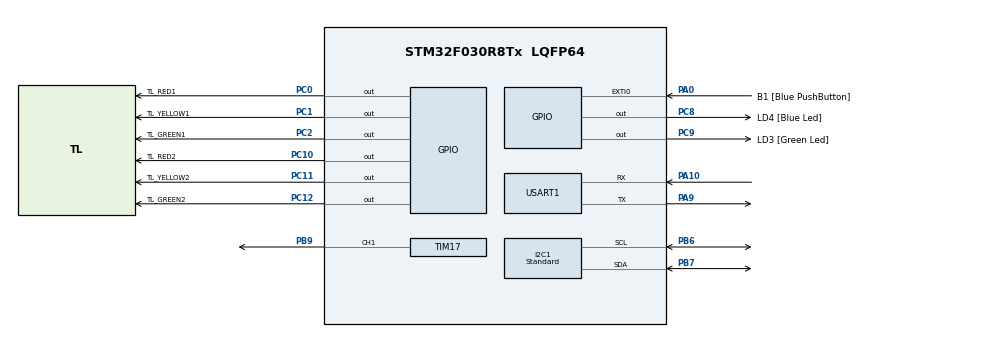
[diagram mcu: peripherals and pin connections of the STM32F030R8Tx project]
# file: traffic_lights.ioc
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Dma.Request0=USART1_RX
Dma.Request1=USART1_TX
Dma.USART1_RX.0.Direction=DMA_PERIPH_TO_MEMORY
Dma.USART1_RX.0.Instance=DMA1_Channel3
Dma.USART1_RX.0.MemDataAlignment=DMA_MDATAALIGN_BYTE
Dma.USART1_RX.0.MemInc=DMA_MINC_ENABLE
Dma.USART1_RX.0.Mode=DMA_NORMAL
Dma.USART1_RX.0.PeriphDataAlignment=DMA_PDATAALIGN_BYTE
Dma.USART1_RX.0.PeriphInc=DMA_PINC_DISABLE
Dma.USART1_RX.0.Priority=DMA_PRIORITY_LOW
Dma.USART1_TX.1.Direction=DMA_MEMORY_TO_PERIPH
Dma.USART1_TX.1.Instance=DMA1_Channel2
Dma.USART1_TX.1.MemDataAlignment=DMA_MDATAALIGN_BYTE
Dma.USART1_TX.1.MemInc=DMA_MINC_ENABLE
Dma.USART1_TX.1.Mode=DMA_NORMAL
Dma.USART1_TX.1.PeriphDataAlignment=DMA_PDATAALIGN_BYTE
Dma.USART1_TX.1.PeriphInc=DMA_PINC_DISABLE
Dma.USART1_TX.1.Priority=DMA_PRIORITY_LOW
I2C1.I2C_Speed_Mode=I2C_Standard
Mcu.Family=STM32F0
Mcu.Name=STM32F030R8Tx
Mcu.Package=LQFP64
NVIC.DMA1_Channel2_3_IRQn=true\:0\:0\:false\:true\:true\:2\:false\:true
NVIC.EXTI0_1_IRQn=true\:0\:0\:false\:true\:true\:3\:true\:true
NVIC.TIM16_IRQn=true\:0\:0\:false\:false\:true\:true\:true
NVIC.TIM6_IRQn=true\:0\:0\:false\:true\:true\:1\:true\:true
NVIC.USART1_IRQn=true\:0\:0\:false\:false\:true\:true\:true
PA0.GPIO_Label=B1 [Blue PushButton]
PA0.GPIO_ModeDefaultEXTI=GPIO_MODE_IT_FALLING
PA0.GPIO_PuPd=GPIO_NOPULL
PA0.Signal=GPXTI0
PA10.Mode=Asynchronous
PA10.Signal=USART1_RX
PA13.GPIO_Label=SWDIO
PA13.Mode=Serial_Wire
PA13.Signal=SYS_SWDIO
PA14.GPIO_Label=SWCLK
PA14.Mode=Serial_Wire
PA14.Signal=SYS_SWCLK
PA9.Mode=Asynchronous
PA9.Signal=USART1_TX
PB6.Mode=I2C
PB6.Signal=I2C1_SCL
PB7.Mode=I2C
PB7.Signal=I2C1_SDA
PB9.Signal=S_TIM17_CH1
PC0.GPIO_Label=TL_RED1
PC0.PinState=GPIO_PIN_SET
PC0.Signal=GPIO_Output
PC1.GPIO_Label=TL_YELLOW1
PC1.PinState=GPIO_PIN_SET
PC1.Signal=GPIO_Output
PC10.GPIO_Label=TL_RED2
PC10.Signal=GPIO_Output
PC11.GPIO_Label=TL_YELLOW2
PC11.Signal=GPIO_Output
PC12.GPIO_Label=TL_GREEN2
PC12.Signal=GPIO_Output
PC2.GPIO_Label=TL_GREEN1
PC2.PinState=GPIO_PIN_SET
PC2.Signal=GPIO_Output
PC8.GPIO_Label=LD4 [Blue Led]
PC8.Signal=GPIO_Output
PC9.GPIO_Label=LD3 [Green Led]
PC9.Signal=GPIO_Output
ProjectManager.HeapSize=0x200
ProjectManager.StackSize=0x400
ProjectManager.TargetToolchain=EWARM V8.32
RCC.AHBFreq_Value=48000000
RCC.APB1Freq_Value=48000000
RCC.APB1TimFreq_Value=48000000
RCC.HCLKFreq_Value=48000000
RCC.PLLMUL=RCC_PLL_MUL12
RCC.SYSCLKFreq_VALUE=48000000
RCC.SYSCLKSource=RCC_SYSCLKSOURCE_PLLCLK
SH.S_TIM17_CH1.0=TIM17_CH1,PWM Generation1 CH1
TIM16.Period=2
TIM16.Prescaler=19-1
TIM17.Channel=TIM_CHANNEL_1
TIM17.Period=2
TIM17.Prescaler=19 - 1
TIM17.Pulse=4
TIM6.Period=599
TIM6.Prescaler=5999
USART1.VirtualMode-Asynchronous=VM_ASYNC
VP_TIM16_VS_ClockSourceINT.Mode=Enable_Timer
VP_TIM17_VS_ClockSourceINT.Mode=Enable_Timer
VP_TIM6_VS_ClockSourceINT.Mode=Enable_Timer
board=STM32F0308-DISCO

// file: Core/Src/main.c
/* USER CODE BEGIN Header */
/**
  ******************************************************************************
  * @file           : main.c
  * @brief          : Main program body
  ******************************************************************************
  * @attention
  *
  * <h2><center>&copy; Copyright (c) 2020 STMicroelectronics.
  * All rights reserved.</center></h2>
  *
  * This software component is licensed by ST under BSD 3-Clause license,
  * the "License"; You may not use this file except in compliance with the
  * License. You may obtain a copy of the License at:
  *                        opensource.org/licenses/BSD-3-Clause
  *
  ******************************************************************************
  */
/* USER CODE END Header */
#include "main.h"

/* USER CODE BEGIN Includes */
#include <stdio.h>
#include "amg8833_driver.h"
#include "mlx90614_driver.h"
/* USER CODE END Includes */

/* USER CODE BEGIN PD */
#define UART_STRING_LEN 7
/* USER CODE END PD */

I2C_HandleTypeDef hi2c1;

TIM_HandleTypeDef htim6;
TIM_HandleTypeDef htim16;
TIM_HandleTypeDef htim17;

UART_HandleTypeDef huart1;
DMA_HandleTypeDef hdma_usart1_rx;
DMA_HandleTypeDef hdma_usart1_tx;

/* USER CODE BEGIN PV */
tl_states_s sequence_counter;
trl_states_s color_counter;
uint16_t termo_pic[64];
uint32_t led_color_ram[WS2812B_LEDS];
/* USER CODE END PV */

void SystemClock_Config(void);
static void MX_GPIO_Init(void);
static void MX_DMA_Init(void);
static void MX_TIM6_Init(void);
static void MX_USART1_UART_Init(void);
static void MX_I2C1_Init(void);
static void MX_TIM17_Init(void);
static void MX_TIM16_Init(void);
static void MX_NVIC_Init(void);
/* USER CODE BEGIN PFP */
uint32_t WD1282_set_color(uint8_t red, uint8_t green, uint8_t blue);
/* USER CODE END PFP */

int main(void)
{
  /* USER CODE BEGIN 1 */
  //int i, j;
  float temp;
  char buffer_tx[UART_STRING_LEN];
  /* USER CODE END 1 */

  /* MCU Configuration--------------------------------------------------------*/

  /* Reset of all peripherals, Initializes the Flash interface and the Systick. */
  HAL_Init();

  /* Configure the system clock */
  SystemClock_Config();

  /* Initialize all configured peripherals */
  MX_GPIO_Init();
  MX_DMA_Init();
  MX_TIM6_Init();
  MX_USART1_UART_Init();
  MX_I2C1_Init();
  MX_TIM17_Init();
  MX_TIM16_Init();

  /* Initialize interrupts */
  MX_NVIC_Init();
  /* USER CODE BEGIN 2 */
  sequence_counter = TL_OFF;
  color_counter = OFF;
  HAL_GPIO_WritePin(GPIOC, TL_RED1_Pin|TL_YELLOW1_Pin|TL_GREEN1_Pin, GPIO_PIN_SET);
  //HAL_TIM_PWM_Start(&htim17, TIM_CHANNEL_1);
  //HAL_TIM_Base_Start_IT(&htim16);
  /* USER CODE END 2 */

  /* Infinite loop */
  /* USER CODE BEGIN WHILE */

  while (1)
  {
    if ( HAL_OK == mlx90614GetObjectTemp(&hi2c1, &temp))
    {
      sprintf(buffer_tx, "v%2d%d", (int) temp, (int)  ((temp - (int) temp) * 100));
      buffer_tx[5] = 0x77;
      buffer_tx[6] = 0x02;
      HAL_UART_Transmit(&huart1, (uint8_t *) buffer_tx, UART_STRING_LEN, 100);
      HAL_Delay(2000);
     }
    if ( HAL_OK == mlx90614GetEnviromentTemp(&hi2c1, &temp))
    {
      sprintf(buffer_tx, "v%2d%d", (int) temp, (int)  ((temp - (int) temp) * 100));
      buffer_tx[5] = 0x77;
      buffer_tx[6] = 0x02;
      HAL_UART_Transmit(&huart1, (uint8_t *) buffer_tx, UART_STRING_LEN, 100);
      HAL_Delay(2000);
     }

    /* USER CODE END WHILE */

  }
}

void SystemClock_Config(void)
{
  RCC_OscInitTypeDef RCC_OscInitStruct = {0};
  RCC_ClkInitTypeDef RCC_ClkInitStruct = {0};
  RCC_PeriphCLKInitTypeDef PeriphClkInit = {0};

  /** Initializes the RCC Oscillators according to the specified parameters
  * in the RCC_OscInitTypeDef structure.
  */
  RCC_OscInitStruct.OscillatorType = RCC_OSCILLATORTYPE_HSI;
  RCC_OscInitStruct.HSIState = RCC_HSI_ON;
  RCC_OscInitStruct.HSICalibrationValue = RCC_HSICALIBRATION_DEFAULT;
  RCC_OscInitStruct.PLL.PLLState = RCC_PLL_ON;
  RCC_OscInitStruct.PLL.PLLSource = RCC_PLLSOURCE_HSI;
  RCC_OscInitStruct.PLL.PLLMUL = RCC_PLL_MUL4;
  RCC_OscInitStruct.PLL.PREDIV = RCC_PREDIV_DIV1;
  if (HAL_RCC_OscConfig(&RCC_OscInitStruct) != HAL_OK)
  {
    Error_Handler();
  }
  /** Initializes the CPU, AHB and APB buses clocks
  */
  RCC_ClkInitStruct.ClockType = RCC_CLOCKTYPE_HCLK|RCC_CLOCKTYPE_SYSCLK
                              |RCC_CLOCKTYPE_PCLK1;
  RCC_ClkInitStruct.SYSCLKSource = RCC_SYSCLKSOURCE_PLLCLK;
  RCC_ClkInitStruct.AHBCLKDivider = RCC_SYSCLK_DIV2;
  RCC_ClkInitStruct.APB1CLKDivider = RCC_HCLK_DIV1;

  if (HAL_RCC_ClockConfig(&RCC_ClkInitStruct, FLASH_LATENCY_0) != HAL_OK)
  {
    Error_Handler();
  }
  PeriphClkInit.PeriphClockSelection = RCC_PERIPHCLK_USART1|RCC_PERIPHCLK_I2C1;
  PeriphClkInit.Usart1ClockSelection = RCC_USART1CLKSOURCE_PCLK1;
  PeriphClkInit.I2c1ClockSelection = RCC_I2C1CLKSOURCE_HSI;
  if (HAL_RCCEx_PeriphCLKConfig(&PeriphClkInit) != HAL_OK)
  {
    Error_Handler();
  }
}

/**
  * @brief NVIC Configuration.
  * @retval None
  */
static void MX_NVIC_Init(void)
{
  /* TIM6_IRQn interrupt configuration */
  HAL_NVIC_SetPriority(TIM6_IRQn, 0, 0);
  HAL_NVIC_EnableIRQ(TIM6_IRQn);
  /* DMA1_Channel2_3_IRQn interrupt configuration */
  HAL_NVIC_SetPriority(DMA1_Channel2_3_IRQn, 0, 0);
  HAL_NVIC_EnableIRQ(DMA1_Channel2_3_IRQn);
  /* EXTI0_1_IRQn interrupt configuration */
  HAL_NVIC_SetPriority(EXTI0_1_IRQn, 0, 0);
  HAL_NVIC_EnableIRQ(EXTI0_1_IRQn);
}

static void MX_I2C1_Init(void)
{

  hi2c1.Instance = I2C1;
  hi2c1.Init.Timing = 0x2000090E;
  hi2c1.Init.OwnAddress1 = 0;
  hi2c1.Init.AddressingMode = I2C_ADDRESSINGMODE_7BIT;
  hi2c1.Init.DualAddressMode = I2C_DUALADDRESS_DISABLE;
  hi2c1.Init.OwnAddress2 = 0;
  hi2c1.Init.OwnAddress2Masks = I2C_OA2_NOMASK;
  hi2c1.Init.GeneralCallMode = I2C_GENERALCALL_DISABLE;
  hi2c1.Init.NoStretchMode = I2C_NOSTRETCH_DISABLE;
  if (HAL_I2C_Init(&hi2c1) != HAL_OK)
  {
    Error_Handler();
  }
  /** Configure Analogue filter
  */
  if (HAL_I2CEx_ConfigAnalogFilter(&hi2c1, I2C_ANALOGFILTER_ENABLE) != HAL_OK)
  {
    Error_Handler();
  }
  /** Configure Digital filter
  */
  if (HAL_I2CEx_ConfigDigitalFilter(&hi2c1, 0) != HAL_OK)
  {
    Error_Handler();
  }

}

static void MX_TIM6_Init(void)
{

  htim6.Instance = TIM6;
  htim6.Init.Prescaler = 5999;
  htim6.Init.CounterMode = TIM_COUNTERMODE_UP;
  htim6.Init.Period = 599;
  htim6.Init.AutoReloadPreload = TIM_AUTORELOAD_PRELOAD_DISABLE;
  if (HAL_TIM_Base_Init(&htim6) != HAL_OK)
  {
    Error_Handler();
  }

}

static void MX_TIM16_Init(void)
{

  htim16.Instance = TIM16;
  htim16.Init.Prescaler = 1-1;
  htim16.Init.CounterMode = TIM_COUNTERMODE_UP;
  htim16.Init.Period = 9;
  htim16.Init.ClockDivision = TIM_CLOCKDIVISION_DIV1;
  htim16.Init.RepetitionCounter = 0;
  htim16.Init.AutoReloadPreload = TIM_AUTORELOAD_PRELOAD_DISABLE;
  if (HAL_TIM_Base_Init(&htim16) != HAL_OK)
  {
    Error_Handler();
  }

}

static void MX_TIM17_Init(void)
{

  TIM_OC_InitTypeDef sConfigOC = {0};
  TIM_BreakDeadTimeConfigTypeDef sBreakDeadTimeConfig = {0};

  htim17.Instance = TIM17;
  htim17.Init.Prescaler = 1 - 1;
  htim17.Init.CounterMode = TIM_COUNTERMODE_UP;
  htim17.Init.Period = 9;
  htim17.Init.ClockDivision = TIM_CLOCKDIVISION_DIV1;
  htim17.Init.RepetitionCounter = 0;
  htim17.Init.AutoReloadPreload = TIM_AUTORELOAD_PRELOAD_DISABLE;
  if (HAL_TIM_Base_Init(&htim17) != HAL_OK)
  {
    Error_Handler();
  }
  if (HAL_TIM_PWM_Init(&htim17) != HAL_OK)
  {
    Error_Handler();
  }
  sConfigOC.OCMode = TIM_OCMODE_PWM1;
  sConfigOC.Pulse = 4;
  sConfigOC.OCPolarity = TIM_OCPOLARITY_HIGH;
  sConfigOC.OCNPolarity = TIM_OCNPOLARITY_HIGH;
  sConfigOC.OCFastMode = TIM_OCFAST_DISABLE;
  sConfigOC.OCIdleState = TIM_OCIDLESTATE_RESET;
  sConfigOC.OCNIdleState = TIM_OCNIDLESTATE_RESET;
  if (HAL_TIM_PWM_ConfigChannel(&htim17, &sConfigOC, TIM_CHANNEL_1) != HAL_OK)
  {
    Error_Handler();
  }
  sBreakDeadTimeConfig.OffStateRunMode = TIM_OSSR_DISABLE;
  sBreakDeadTimeConfig.OffStateIDLEMode = TIM_OSSI_DISABLE;
  sBreakDeadTimeConfig.LockLevel = TIM_LOCKLEVEL_OFF;
  sBreakDeadTimeConfig.DeadTime = 0;
  sBreakDeadTimeConfig.BreakState = TIM_BREAK_DISABLE;
  sBreakDeadTimeConfig.BreakPolarity = TIM_BREAKPOLARITY_HIGH;
  sBreakDeadTimeConfig.AutomaticOutput = TIM_AUTOMATICOUTPUT_DISABLE;
  if (HAL_TIMEx_ConfigBreakDeadTime(&htim17, &sBreakDeadTimeConfig) != HAL_OK)
  {
    Error_Handler();
  }
  HAL_TIM_MspPostInit(&htim17);

}

static void MX_USART1_UART_Init(void)
{

  huart1.Instance = USART1;
  huart1.Init.BaudRate = 9600;
  huart1.Init.WordLength = UART_WORDLENGTH_8B;
  huart1.Init.StopBits = UART_STOPBITS_1;
  huart1.Init.Parity = UART_PARITY_NONE;
  huart1.Init.Mode = UART_MODE_TX_RX;
  huart1.Init.HwFlowCtl = UART_HWCONTROL_NONE;
  huart1.Init.OverSampling = UART_OVERSAMPLING_16;
  huart1.Init.OneBitSampling = UART_ONE_BIT_SAMPLE_DISABLE;
  huart1.AdvancedInit.AdvFeatureInit = UART_ADVFEATURE_NO_INIT;
  if (HAL_UART_Init(&huart1) != HAL_OK)
  {
    Error_Handler();
  }

}

static void MX_DMA_Init(void)
{

  /* DMA controller clock enable */
  __HAL_RCC_DMA1_CLK_ENABLE();

}

static void MX_GPIO_Init(void)
{
  GPIO_InitTypeDef GPIO_InitStruct = {0};

  /* GPIO Ports Clock Enable */
  __HAL_RCC_GPIOC_CLK_ENABLE();
  __HAL_RCC_GPIOA_CLK_ENABLE();
  __HAL_RCC_GPIOB_CLK_ENABLE();

  /*Configure GPIO pin Output Level */
  HAL_GPIO_WritePin(GPIOC, TL_RED1_Pin|TL_YELLOW1_Pin|TL_GREEN1_Pin, GPIO_PIN_SET);

  /*Configure GPIO pin Output Level */
  HAL_GPIO_WritePin(GPIOC, LD4_Pin|LD3_Pin|TL_RED2_Pin|TL_YELLOW2_Pin
                          |TL_GREEN2_Pin, GPIO_PIN_RESET);

  /*Configure GPIO pins : TL_RED1_Pin TL_YELLOW1_Pin TL_GREEN1_Pin LD4_Pin
                           LD3_Pin TL_RED2_Pin TL_YELLOW2_Pin TL_GREEN2_Pin */
  GPIO_InitStruct.Pin = TL_RED1_Pin|TL_YELLOW1_Pin|TL_GREEN1_Pin|LD4_Pin
                          |LD3_Pin|TL_RED2_Pin|TL_YELLOW2_Pin|TL_GREEN2_Pin;
  GPIO_InitStruct.Mode = GPIO_MODE_OUTPUT_PP;
  GPIO_InitStruct.Pull = GPIO_NOPULL;
  GPIO_InitStruct.Speed = GPIO_SPEED_FREQ_LOW;
  HAL_GPIO_Init(GPIOC, &GPIO_InitStruct);

  /*Configure GPIO pin : B1_Pin */
  GPIO_InitStruct.Pin = B1_Pin;
  GPIO_InitStruct.Mode = GPIO_MODE_IT_FALLING;
  GPIO_InitStruct.Pull = GPIO_NOPULL;
  HAL_GPIO_Init(B1_GPIO_Port, &GPIO_InitStruct);

}

/* USER CODE BEGIN 4 */
uint32_t WD1282_set_color(uint8_t red, uint8_t green, uint8_t blue)
{
  uint32_t result = 0;
  result = (result | green) << 8;
  result = (result | red) << 8;
  result = (result | blue);
  return result;
}
/* USER CODE END 4 */

void Error_Handler(void)
{
}

/************************ (C) COPYRIGHT STMicroelectronics *****END OF FILE****/
